VERSION 5.7 ;
  NOWIREEXTENSIONATPIN ON ;
  DIVIDERCHAR "/" ;
  BUSBITCHARS "[]" ;
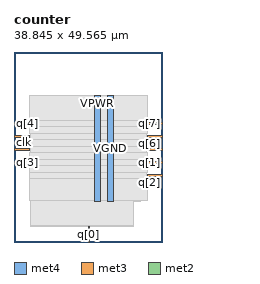
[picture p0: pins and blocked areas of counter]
MACRO counter
  CLASS BLOCK ;
  FOREIGN counter ;
  ORIGIN 0.000 0.000 ;
  SIZE 38.845 BY 49.565 ;
  PIN VGND
    DIRECTION INOUT ;
    USE GROUND ;
    PORT
      LAYER met4 ;
        RECT 24.340 10.640 25.940 38.320 ;
    END
  END VGND
  PIN VPWR
    DIRECTION INOUT ;
    USE POWER ;
    PORT
      LAYER met4 ;
        RECT 21.040 10.640 22.640 38.320 ;
    END
  END VPWR
  PIN clk
    DIRECTION INPUT ;
    USE SIGNAL ;
    ANTENNAGATEAREA 0.852000 ;
    PORT
      LAYER met3 ;
        RECT 0.000 23.840 4.000 24.440 ;
    END
  END clk
  PIN q[0]
    DIRECTION OUTPUT ;
    USE SIGNAL ;
    ANTENNADIFFAREA 0.445500 ;
    PORT
      LAYER met2 ;
        RECT 19.410 0.000 19.690 4.000 ;
    END
  END q[0]
  PIN q[1]
    DIRECTION OUTPUT ;
    USE SIGNAL ;
    ANTENNADIFFAREA 0.445500 ;
    PORT
      LAYER met3 ;
        RECT 34.845 20.440 38.845 21.040 ;
    END
  END q[1]
  PIN q[2]
    DIRECTION OUTPUT ;
    USE SIGNAL ;
    ANTENNADIFFAREA 0.445500 ;
    PORT
      LAYER met3 ;
        RECT 34.845 17.040 38.845 17.640 ;
    END
  END q[2]
  PIN q[3]
    DIRECTION OUTPUT ;
    USE SIGNAL ;
    ANTENNADIFFAREA 0.445500 ;
    PORT
      LAYER met3 ;
        RECT 0.000 20.440 4.000 21.040 ;
    END
  END q[3]
  PIN q[4]
    DIRECTION OUTPUT ;
    USE SIGNAL ;
    ANTENNADIFFAREA 0.445500 ;
    PORT
      LAYER met3 ;
        RECT 0.000 30.640 4.000 31.240 ;
    END
  END q[4]
  PIN q[5]
    DIRECTION OUTPUT ;
    USE SIGNAL ;
    ANTENNADIFFAREA 0.445500 ;
    PORT
      LAYER met3 ;
        RECT 0.000 27.240 4.000 27.840 ;
    END
  END q[5]
  PIN q[6]
    DIRECTION OUTPUT ;
    USE SIGNAL ;
    ANTENNADIFFAREA 0.445500 ;
    PORT
      LAYER met3 ;
        RECT 34.845 27.240 38.845 27.840 ;
    END
  END q[6]
  PIN q[7]
    DIRECTION OUTPUT ;
    USE SIGNAL ;
    ANTENNADIFFAREA 0.445500 ;
    PORT
      LAYER met3 ;
        RECT 34.845 30.640 38.845 31.240 ;
    END
  END q[7]
  PIN rst
    DIRECTION INPUT ;
    USE SIGNAL ;
    ANTENNAGATEAREA 0.213000 ;
    PORT
      LAYER met3 ;
        RECT 34.845 23.840 38.845 24.440 ;
    END
  END rst
  OBS
      LAYER nwell ;
        RECT 5.330 10.795 33.310 38.165 ;
      LAYER li1 ;
        RECT 5.520 10.795 33.120 38.165 ;
      LAYER met1 ;
        RECT 4.210 10.640 33.120 38.320 ;
      LAYER met2 ;
        RECT 4.230 4.280 31.180 38.265 ;
        RECT 4.230 4.000 19.130 4.280 ;
        RECT 19.970 4.000 31.180 4.280 ;
      LAYER met3 ;
        RECT 3.990 31.640 34.845 38.245 ;
        RECT 4.400 30.240 34.445 31.640 ;
        RECT 3.990 28.240 34.845 30.240 ;
        RECT 4.400 26.840 34.445 28.240 ;
        RECT 3.990 24.840 34.845 26.840 ;
        RECT 4.400 23.440 34.445 24.840 ;
        RECT 3.990 21.440 34.845 23.440 ;
        RECT 4.400 20.040 34.445 21.440 ;
        RECT 3.990 18.040 34.845 20.040 ;
        RECT 3.990 16.640 34.445 18.040 ;
        RECT 3.990 10.715 34.845 16.640 ;
  END
END counter
END LIBRARY

